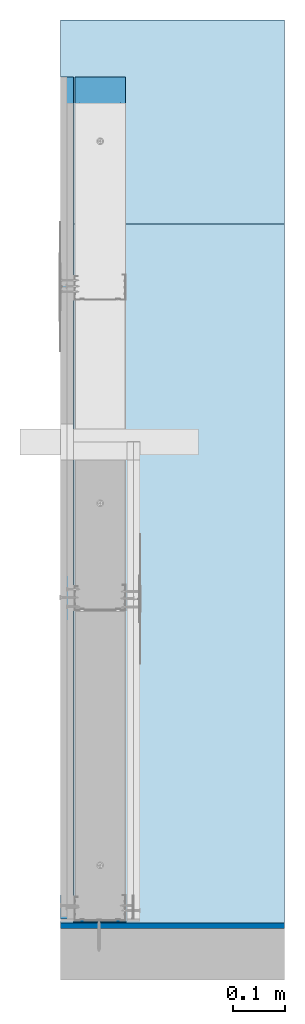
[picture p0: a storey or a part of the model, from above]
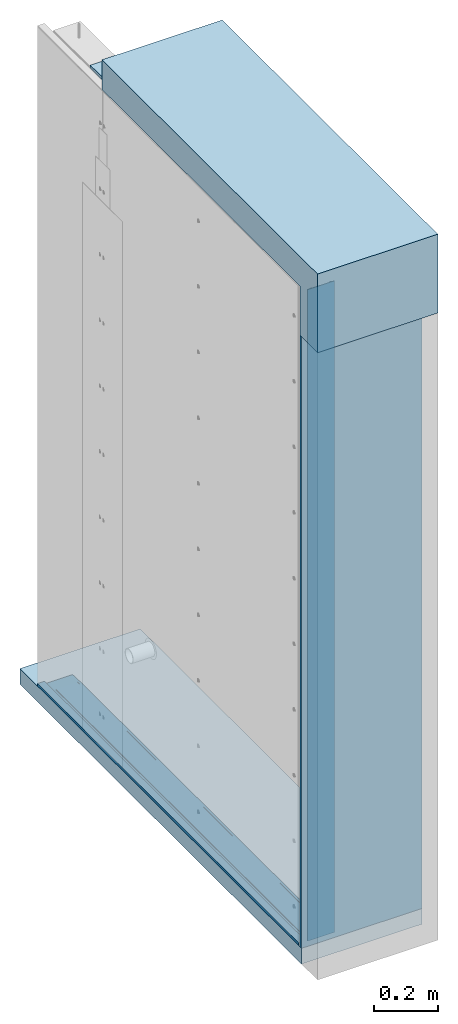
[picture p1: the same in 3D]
Properties of the parts of a building model (IFC2X3)

# File
Description: ViewDefinition [CoordinationView_V2.0]
File name: kolizja nr 6 - 2018.ifc
Time: 2025-11-21T11:42:13
Written by: IFC-manager for SketchUp (5.5.4)
Made in: SketchUp 2026 (26.0.429)

# IfcSite, Default Site
RefElevation: 0 mm

# IfcBuilding, Default Building
ElevationOfRefHeight: 0 mm; ElevationOfTerrain: 0 mm

# IfcBuildingStorey, Default Building Storey
In: Default Building
Elevation: 0 mm
Parametry kolizji SG - Elementkolizyjnykonstrukcyjnyinstalacyjny: Rura instalacyjna o małej średnicy; ElementsystemuSaintGobain: Ściana działowa; Izolacyjnoscakustyczna: niezweryfikowana; Klasaodpornosciogniowej: -; LODlevelofDevelopment: 400; Nrdetalu: 5.57.02; Opis: Detal przejścia rury o małej średnicy przez ścianę działową wykonaną w systemie RIGIPS; Producent: SAINT-GOBAIN; Sposobwykonania: W przypadku koniecznoÅ›ci poprowadzenia przewodu rurowego o maÅ‚ej Å›rednicy ( Ã˜<25mm) przez Å›cianÄ™ dziaÅ‚owÄ… w systemie RIGIPS naleÅ¼y zaprojektowaÄ‡ jego przebieg w taki sposÃ³b, aby nie kolidowaÅ‚ z profilami pionowymi CW. JeÅ¼eli kolizja z profilem CW jest nieunikniona, naleÅ¼y przewidzieÄ‡ i wykonaÄ‡ w Å›cianie dodatkowy profil pionowy CW, zapewniajÄ…cy prawidÅ‚owe usztywnienie konstrukcji. W miejscu przejÅ›cia instalacji naleÅ¼y wykonaÄ‡ otwÃ³r okrÄ…gÅ‚y w pÅ‚ytach gipsowo-kartonowych o wymiarach wiÄ™kszych od Å›rednicy rury o 10â€“20 mm. PrzestrzeÅ„ pomiÄ™dzy krawÄ™dziÄ… rury a krawÄ™dziÄ… otworu naleÅ¼y wypeÅ‚niÄ‡ weÅ‚nÄ… mineralnÄ… ISOVER, a nastÄ™pnie na wypeÅ‚nienie zastosowaÄ‡ masÄ™ szpachlowÄ… RIGIPS, zapewniajÄ…c szczelne i estetyczne wykoÅ„czenie powierzchni Å›ciany.; Typkolizji: twarda; Warianty: -

# IfcSlab: Beton#1, Beton
In: Default Building Storey
Type - PredefinedType: FLOOR
Material: Concrete_02_1K
Qto_SlabBaseQuantities - NetVolume: 0.045624 m3; Depth: 59.9996 mm; NetArea: 0.760405 m2

# IfcSlab: Strop#1, Strop
In: Default Building Storey
Type - PredefinedType: FLOOR
Material: Concrete_02_1K

# IfcSlab: Strop#3, Strop
In: Default Building Storey
Type - PredefinedType: FLOOR
Material: M04_Stone_Frost
Qto_SlabBaseQuantities - NetVolume: 0.00633228 m3; Depth: 200 mm; NetArea: 0.0316614 m2

# IfcWall: Kołek rozporowy min. fi 6 (12)
In: Default Building Storey
Type - Description: Description of Object
Material: Default

# IfcWall: Kołek rozporowy min. fi 6#1 (12)
In: Default Building Storey
Type - Description: Description of Object
Material: Default

# IfcWall: Masa szpachlowa konstrukcyjna RIGIPS#10, Masa szpachlowa konstrukcyjna RIGIPS
In: Default Building Storey
Type - Description: Description of Object
Material: Undefined5
Qto_WallBaseQuantities - NetVolume: 0.000203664 m3

# IfcWall: Masa szpachlowa konstrukcyjna RIGIPS#11, Masa szpachlowa konstrukcyjna RIGIPS
In: Default Building Storey
Type - Description: Description of Object
Material: Undefined5
Qto_WallBaseQuantities - NetVolume: 0.000314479 m3

# IfcWall: Masa szpachlowa konstrukcyjna RIGIPS#12, Masa szpachlowa konstrukcyjna RIGIPS
In: Default Building Storey
Type - Description: Description of Object
Material: Default

# IfcWall: Masa szpachlowa konstrukcyjna RIGIPS#13, Masa szpachlowa konstrukcyjna RIGIPS
In: Default Building Storey
Type - Description: Description of Object
Material: Undefined5
Qto_WallBaseQuantities - NetVolume: 0.000230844 m3

# IfcWall: Masa szpachlowa konstrukcyjna RIGIPS#4, Masa szpachlowa konstrukcyjna RIGIPS
In: Default Building Storey
Type - Description: Description of Object
Material: Undefined5
Qto_WallBaseQuantities - NetVolume: 0.000314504 m3

# IfcWall: Masa szpachlowa konstrukcyjna RIGIPS#6, Masa szpachlowa konstrukcyjna RIGIPS
In: Default Building Storey
Type - Description: Description of Object
Material: Default

# IfcWall: Masa szpachlowa konstrukcyjna RIGIPS#7, Masa szpachlowa konstrukcyjna RIGIPS
In: Default Building Storey
Type - Description: Description of Object
Material: Undefined5
Qto_WallBaseQuantities - NetVolume: 0.000407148 m3

# IfcWall: Masa szpachlowa konstrukcyjna RIGIPS#9, Masa szpachlowa konstrukcyjna RIGIPS
In: Default Building Storey
Type - Description: Description of Object
Material: Undefined5
Qto_WallBaseQuantities - NetVolume: 0.0000493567 m3; Width: 2.88725 mm; Length: 45 mm; NetSideArea: 0.0170947 m2

# IfcWall: Masa szpachlowa wykończeniowa RIGIPS
In: Default Building Storey
Type - Description: Description of Object
Material: Default

# IfcWall: Masa szpachlowa wykończeniowa RIGIPS#2, Masa szpachlowa wykończeniowa RIGIPS
In: Default Building Storey
Type - Description: Description of Object
Material: Default

# IfcWall: Profil Rigips CW 100 GypSerra®/Ultrastil® (3)
In: Default Building Storey
Type - Description: Description of Object
Type - PropertySets - TempShadowInfo: Boulder (CO)
Material: Undefined4

# IfcWall: Profil Rigips UW 100 GypSerra®/Ultrastil®
In: Default Building Storey
Type - Description: Description of Object
Material: Undefined
Qto_WallBaseQuantities - NetVolume: 0.000156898 m3; Width: 40 mm; Length: 100 mm; NetSideArea: 0.00392246 m2

# IfcWall: Profil Rigips UW 100 GypSerra®/Ultrastil®#3, Profil Rigips UW 100 GypSerra®/Ultrastil®
In: Default Building Storey
Type - Description: Description of Object
Material: Undefined
Qto_WallBaseQuantities - NetVolume: 0.000156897 m3; Width: 40 mm; Length: 100 mm; NetSideArea: 0.00392243 m2

# IfcWall: Przewód instalacyjny - okrągły#1, Przewód instalacyjny - okrągły
In: Default Building Storey
Material: M00_Soft_Cloud
Qto_WallBaseQuantities - NetVolume: 0.0000788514 m3

# IfcWall: Płyta gipsowo-kartonowa RIGIPS PRO (4PRO™)#1, Płyta gipsowo-kartonowa RIGIPS PRO (4PRO™)
In: Default Building Storey
Type - Description: Description of Object
Material: Undefined6
Qto_WallBaseQuantities - NetVolume: 0.0297538 m3; Width: 12.5 mm; Length: 957.116 mm; NetSideArea: 2.3803 m2

# IfcWall: Płyta gipsowo-kartonowa RIGIPS PRO (4PRO™)#10, Płyta gipsowo-kartonowa RIGIPS PRO (4PRO™)
In: Default Building Storey
Type - Description: Description of Object
Material: Undefined6
Qto_WallBaseQuantities - NetVolume: 0.0192673 m3; Width: 12.5 mm; Length: 620.011 mm; NetSideArea: 1.54138 m2

# IfcWall: Płyta gipsowo-kartonowa RIGIPS PRO (4PRO™)#3, Płyta gipsowo-kartonowa RIGIPS PRO (4PRO™)
In: Default Building Storey
Type - Description: Description of Object
Material: Undefined6
Qto_WallBaseQuantities - NetVolume: 0.0377984 m3; Width: 12.5 mm; Length: 1218 mm; NetSideArea: 3.02387 m2

# IfcWall: Płyta gipsowo-kartonowa RIGIPS PRO (4PRO™)#4, Płyta gipsowo-kartonowa RIGIPS PRO (4PRO™)
In: Default Building Storey
Type - Description: Description of Object
Material: Undefined6

# IfcWall: Płyta gipsowo-kartonowa RIGIPS PRO (4PRO™)#6, Płyta gipsowo-kartonowa RIGIPS PRO (4PRO™)
In: Default Building Storey
Type - Description: Description of Object
Material: Undefined6
Qto_WallBaseQuantities - NetVolume: 0.00614187 m3; Width: 12.5 mm; Length: 617.644 mm; NetSideArea: 0.49135 m2

# IfcWall: Płyta gipsowo-kartonowa RIGIPS PRO (4PRO™)#7, Płyta gipsowo-kartonowa RIGIPS PRO (4PRO™)
In: Default Building Storey
Type - Description: Description of Object
Material: Undefined6
Qto_WallBaseQuantities - NetVolume: 0.0125456 m3; Width: 12.5 mm; Length: 404.917 mm; NetSideArea: 1.00365 m2

# IfcWall: Płyta gipsowo-kartonowa RIGIPS PRO (4PRO™)#8, Płyta gipsowo-kartonowa RIGIPS PRO (4PRO™)
In: Default Building Storey
Type - Description: Description of Object
Material: Undefined6

# IfcWall: Taśma spoinowa RIGIPS
In: Default Building Storey
Type - Description: Description of Object
Material: Default

# IfcWall: Taśma spoinowa RIGIPS#2, Taśma spoinowa RIGIPS
In: Default Building Storey
Type - Description: Description of Object
Material: Default

# IfcWall: Taśma uszczelniająca piankowa RIGIPS
In: Default Building Storey
Type - Description: Description of Object
Material: Undefined1
Qto_WallBaseQuantities - NetVolume: 0.000678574 m3

# IfcWall: Taśma uszczelniająca piankowa RIGIPS#3, Taśma uszczelniająca piankowa RIGIPS
In: Default Building Storey
Material: Undefined1

# IfcWall: Taśma uszczelniająca piankowa RIGIPS#5, Taśma uszczelniająca piankowa RIGIPS
In: Default Building Storey
Type - Description: Description of Object
Material: Undefined1

# IfcWall: Uszczelnienie wełną mineralną ISOVER#2, Uszczelnienie wełną mineralną ISOVER
In: Default Building Storey
Material: D02_Buttercup_Glow
Qto_WallBaseQuantities - NetVolume: 0.000152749 m3

# IfcWall: Wełna mineralna szklana lub skalna ISOVER
In: Default Building Storey
Type - Description: Description of Object
Material: Undefined7
Qto_WallBaseQuantities - NetVolume: 0.0578537 m3; Width: 95.8097 mm; Length: 597.65 mm; NetSideArea: 0.603839 m2

# IfcWall: Wełna mineralna szklana lub skalna ISOVER#3, Wełna mineralna szklana lub skalna ISOVER
In: Default Building Storey
Type - Description: Description of Object
Material: Undefined7
Qto_WallBaseQuantities - NetVolume: 0.0542256 m3; Width: 95.8097 mm; Length: 597.65 mm; NetSideArea: 0.565972 m2

# IfcWall: Wełna mineralna szklana lub skalna ISOVER#5, Wełna mineralna szklana lub skalna ISOVER
In: Default Building Storey
Type - Description: Description of Object
Material: Undefined7
Qto_WallBaseQuantities - NetVolume: 0.029456 m3; Width: 95.8097 mm; Length: 324.65 mm; NetSideArea: 0.307442 m2

# IfcWall: Wełna mineralna szklana lub skalna ISOVER#6, Wełna mineralna szklana lub skalna ISOVER
In: Default Building Storey
Type - Description: Description of Object
Material: Undefined7
Qto_WallBaseQuantities - NetVolume: 0.0411536 m3; Width: 95.8097 mm; Length: 599.45 mm; NetSideArea: 0.429535 m2

# IfcWall: Wkręt RIGIPS TN 25#1 (2)
In: Default Building Storey
Type - Description: Description of Object
Material: Default

# IfcWall: Wkręt RIGIPS TN 25#16 (11)
In: Default Building Storey
Type - Description: Description of Object
Material: Default

# IfcWall: Wkręt RIGIPS TN 25#17, Wkręt RIGIPS TN 25
In: Default Building Storey
Type - Description: Description of Object
Material: Default

# IfcWall: Wkręt RIGIPS TN 25#18, Wkręt RIGIPS TN 25
In: Default Building Storey
Type - Description: Description of Object
Material: Default

# IfcWall: Wkręt RIGIPS TN 25#19 (3)
In: Default Building Storey
Type - Description: Description of Object
Material: Default

# IfcWall: Wkręt RIGIPS TN 25#8, Wkręt RIGIPS TN 25
In: Default Building Storey
Type - Description: Description of Object
Material: Default

# IfcWall: Wkręt RIGIPS TN 25#9, Wkręt RIGIPS TN 25
In: Default Building Storey
Type - Description: Description of Object
Material: Default

# IfcWall: Wkręt RIGIPS TN 35#29 (3)
In: Default Building Storey
Type - Description: Description of Object
Material: Default

# IfcWall: Wkręt RIGIPS TN 35#30 (3)
In: Default Building Storey
Type - Description: Description of Object
Material: Default

# IfcWall: Wkręt RIGIPS TN 35#31 (2)
In: Default Building Storey
Type - Description: Description of Object
Material: Undefined2

# IfcWall: Wkręt RIGIPS TN 35#32 (3)
In: Default Building Storey
Type - Description: Description of Object
Material: Default

# IfcWall: Wkręt RIGIPS TN 35#33, Wkręt RIGIPS TN 35
In: Default Building Storey
Type - Description: Description of Object
Material: Undefined2

# IfcWall: Wkręt RIGIPS TN 35#34, Wkręt RIGIPS TN 35
In: Default Building Storey
Type - Description: Description of Object
Material: Default

# IfcWall: Wkręt RIGIPS TN 35#35 (8)
In: Default Building Storey
Type - Description: Description of Object
Material: Undefined2

# IfcWall: Wkręt RIGIPS TN 35#36 (2)
In: Default Building Storey
Type - Description: Description of Object
Material: Undefined2

# IfcWall: Wkręt RIGIPS TN 35#37 (16)
In: Default Building Storey
Type - Description: Description of Object
Material: Undefined2

# IfcWall: Wkręt RIGIPS TN 35#38, Wkręt RIGIPS TN 35
In: Default Building Storey
Type - Description: Description of Object
Material: Undefined2

# IfcWall: Wkręt RIGIPS TN 35#39, Wkręt RIGIPS TN 35
In: Default Building Storey
Type - Description: Description of Object
Material: Default

# IfcWall: Wkręt RIGIPS TN 35#40, Wkręt RIGIPS TN 35
In: Default Building Storey
Type - Description: Description of Object
Material: Default

# IfcWall: Wkręt RIGIPS TN 35#41 (7)
In: Default Building Storey
Type - Description: Description of Object
Material: Default

# IfcWall: Wypełnienie masą szpachlową RIGIPS#2 (2)
In: Default Building Storey
Material: M08_Obsidian_Black
Qto_WallBaseQuantities - NetVolume: 0.0000119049 m3; Width: 12.5 mm; Length: 35 mm; NetSideArea: 0.000952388 m2

# IfcWall: Wypełnienie masą szpachlową RIGIPS#4 (2)
In: Default Building Storey
Material: M08_Obsidian_Black
Qto_WallBaseQuantities - NetVolume: 0.0000238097 m3; Width: 12.5 mm; Length: 70 mm; NetSideArea: 0.00190478 m2

# IfcWall: Ściana#2, Ściana
In: Default Building Storey
Material: M03_Pewter_Shine
Qto_WallBaseQuantities - NetVolume: 0.103401 m3

# IfcWall: Ściana#3, Ściana
In: Default Building Storey
Material: M04_Stone_Frost
Qto_WallBaseQuantities - NetVolume: 0.0100803 m3
